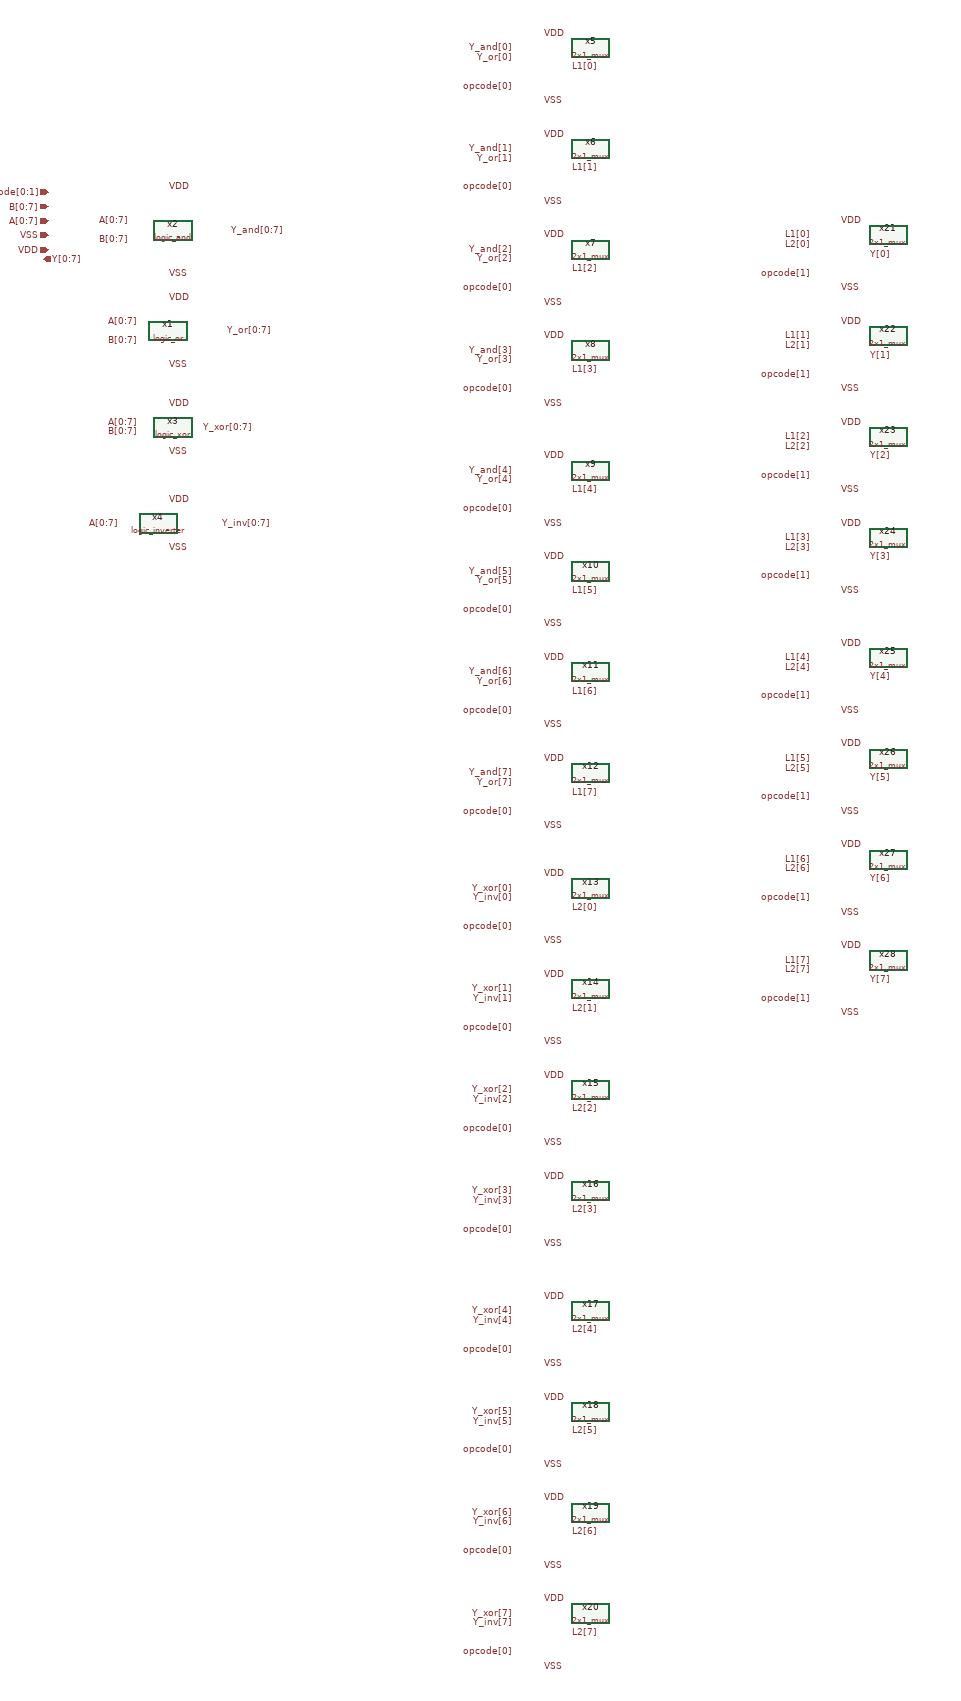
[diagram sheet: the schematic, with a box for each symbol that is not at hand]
v {xschem version=3.1.0 file_version=1.2 }
G {}
K {}
V {}
S {}
E {}
C {logic_or.sym} -820 -830 0 0 {name=x1}
C {logic_and.sym} -810 -1040 0 0 {name=x2}
C {logic_xor.sym} -810 -630 0 0 {name=x3}
C {logic_inverter.sym} -840 -430 0 0 {name=x4}
C {devices/ipin.sym} -1070 -1090 0 0 {name=p4 lab=B[0:7]}
C {devices/opin.sym} -1080 -980 0 0 {name=p9 lab=Y[0:7]}
C {devices/iopin.sym} -1070 -1000 2 0 {name=p2 lab=VDD}
C {devices/iopin.sym} -1070 -1030 2 0 {name=p6 lab=VSS}
C {devices/lab_pin.sym} -900 -1060 0 0 {name=l35 sig_type=std_logic lab=A[0:7]}
C {devices/lab_pin.sym} -900 -1020 0 0 {name=l36 sig_type=std_logic lab=B[0:7]}
C {devices/lab_pin.sym} -880 -850 0 0 {name=l1 sig_type=std_logic lab=A[0:7]}
C {devices/lab_pin.sym} -880 -810 0 0 {name=l2 sig_type=std_logic lab=B[0:7]}
C {devices/lab_pin.sym} -880 -640 0 0 {name=l3 sig_type=std_logic lab=A[0:7]}
C {devices/lab_pin.sym} -880 -620 0 0 {name=l4 sig_type=std_logic lab=B[0:7]}
C {devices/lab_pin.sym} -920 -430 0 0 {name=l5 sig_type=std_logic lab=A[0:7]}
C {devices/lab_pin.sym} -690 -1040 2 0 {name=l37 sig_type=std_logic lab=Y_and[0:7]}
C {devices/lab_pin.sym} -750 -630 2 0 {name=l7 sig_type=std_logic lab=Y_xor[0:7]}
C {devices/lab_pin.sym} -710 -430 2 0 {name=l8 sig_type=std_logic lab=Y_inv[0:7]}
C {devices/lab_pin.sym} -100 -1420 0 0 {name=l9 sig_type=std_logic lab=Y_and[0]}
C {devices/lab_pin.sym} -100 -1210 0 0 {name=l10 sig_type=std_logic lab=Y_and[1]}
C {devices/lab_pin.sym} -100 -1000 0 0 {name=l11 sig_type=std_logic lab=Y_and[2]}
C {devices/lab_pin.sym} -100 -790 0 0 {name=l12 sig_type=std_logic lab=Y_and[3]}
C {devices/lab_pin.sym} -100 -540 0 0 {name=l13 sig_type=std_logic lab=Y_and[4]}
C {devices/lab_pin.sym} -100 -330 0 0 {name=l14 sig_type=std_logic lab=Y_and[5]}
C {devices/lab_pin.sym} -100 -120 0 0 {name=l15 sig_type=std_logic lab=Y_and[6]}
C {devices/lab_pin.sym} -100 90 0 0 {name=l16 sig_type=std_logic lab=Y_and[7]}
C {devices/lab_pin.sym} -100 -1400 0 0 {name=l17 sig_type=std_logic lab=Y_or[0]}
C {devices/lab_pin.sym} -700 -830 2 0 {name=l18 sig_type=std_logic lab=Y_or[0:7]}
C {devices/lab_pin.sym} -100 -1190 0 0 {name=l19 sig_type=std_logic lab=Y_or[1]}
C {devices/lab_pin.sym} -100 -980 0 0 {name=l20 sig_type=std_logic lab=Y_or[2]}
C {devices/lab_pin.sym} -100 -770 0 0 {name=l21 sig_type=std_logic lab=Y_or[3]}
C {devices/lab_pin.sym} -100 -520 0 0 {name=l22 sig_type=std_logic lab=Y_or[4]}
C {devices/lab_pin.sym} -100 -310 0 0 {name=l23 sig_type=std_logic lab=Y_or[5]}
C {devices/lab_pin.sym} -100 -100 0 0 {name=l24 sig_type=std_logic lab=Y_or[6]}
C {devices/lab_pin.sym} -100 110 0 0 {name=l25 sig_type=std_logic lab=Y_or[7]}
C {devices/ipin.sym} -1070 -1120 0 0 {name=p5 lab=opcode[0:1]}
C {devices/lab_pin.sym} -100 -1340 0 0 {name=l26 sig_type=std_logic lab=opcode[0]}
C {devices/lab_pin.sym} -100 -1130 0 0 {name=l27 sig_type=std_logic lab=opcode[0]}
C {devices/lab_pin.sym} -100 -920 0 0 {name=l28 sig_type=std_logic lab=opcode[0]}
C {devices/lab_pin.sym} -100 -710 0 0 {name=l29 sig_type=std_logic lab=opcode[0]}
C {devices/lab_pin.sym} -100 -460 0 0 {name=l30 sig_type=std_logic lab=opcode[0]}
C {devices/lab_pin.sym} -100 -250 0 0 {name=l31 sig_type=std_logic lab=opcode[0]}
C {devices/lab_pin.sym} -100 -40 0 0 {name=l32 sig_type=std_logic lab=opcode[0]}
C {devices/lab_pin.sym} -100 170 0 0 {name=l33 sig_type=std_logic lab=opcode[0]}
C {devices/lab_pin.sym} -100 410 0 0 {name=l34 sig_type=std_logic lab=opcode[0]}
C {devices/lab_pin.sym} -100 620 0 0 {name=l38 sig_type=std_logic lab=opcode[0]}
C {devices/lab_pin.sym} -100 830 0 0 {name=l39 sig_type=std_logic lab=opcode[0]}
C {devices/lab_pin.sym} -100 1040 0 0 {name=l40 sig_type=std_logic lab=opcode[0]}
C {devices/lab_pin.sym} -100 1290 0 0 {name=l41 sig_type=std_logic lab=opcode[0]}
C {devices/lab_pin.sym} -100 1500 0 0 {name=l42 sig_type=std_logic lab=opcode[0]}
C {devices/lab_pin.sym} -100 1710 0 0 {name=l43 sig_type=std_logic lab=opcode[0]}
C {devices/lab_pin.sym} -100 1920 0 0 {name=l44 sig_type=std_logic lab=opcode[0]}
C {devices/lab_pin.sym} -100 330 0 0 {name=l45 sig_type=std_logic lab=Y_xor[0]}
C {devices/lab_pin.sym} -100 540 0 0 {name=l46 sig_type=std_logic lab=Y_xor[1]}
C {devices/lab_pin.sym} -100 750 0 0 {name=l47 sig_type=std_logic lab=Y_xor[2]}
C {devices/lab_pin.sym} -100 960 0 0 {name=l48 sig_type=std_logic lab=Y_xor[3]}
C {devices/lab_pin.sym} -100 1210 0 0 {name=l49 sig_type=std_logic lab=Y_xor[4]}
C {devices/lab_pin.sym} -100 1420 0 0 {name=l50 sig_type=std_logic lab=Y_xor[5]}
C {devices/lab_pin.sym} -100 1630 0 0 {name=l51 sig_type=std_logic lab=Y_xor[6]}
C {devices/lab_pin.sym} -100 1840 0 0 {name=l52 sig_type=std_logic lab=Y_xor[7]}
C {devices/lab_pin.sym} -100 350 0 0 {name=l53 sig_type=std_logic lab=Y_inv[0]}
C {devices/lab_pin.sym} -100 560 0 0 {name=l54 sig_type=std_logic lab=Y_inv[1]}
C {devices/lab_pin.sym} -100 770 0 0 {name=l55 sig_type=std_logic lab=Y_inv[2]}
C {devices/lab_pin.sym} -100 980 0 0 {name=l56 sig_type=std_logic lab=Y_inv[3]}
C {devices/lab_pin.sym} -100 1230 0 0 {name=l57 sig_type=std_logic lab=Y_inv[4]}
C {devices/lab_pin.sym} -100 1440 0 0 {name=l58 sig_type=std_logic lab=Y_inv[5]}
C {devices/lab_pin.sym} -100 1650 0 0 {name=l59 sig_type=std_logic lab=Y_inv[6]}
C {devices/lab_pin.sym} -100 1860 0 0 {name=l60 sig_type=std_logic lab=Y_inv[7]}
C {devices/lab_pin.sym} 520 -950 0 0 {name=l61 sig_type=std_logic lab=opcode[1]}
C {devices/lab_pin.sym} 520 -740 0 0 {name=l62 sig_type=std_logic lab=opcode[1]}
C {devices/lab_pin.sym} 520 -530 0 0 {name=l63 sig_type=std_logic lab=opcode[1]}
C {devices/lab_pin.sym} 520 -320 0 0 {name=l64 sig_type=std_logic lab=opcode[1]}
C {devices/lab_pin.sym} 520 -70 0 0 {name=l65 sig_type=std_logic lab=opcode[1]}
C {devices/lab_pin.sym} 520 140 0 0 {name=l66 sig_type=std_logic lab=opcode[1]}
C {devices/lab_pin.sym} 520 350 0 0 {name=l67 sig_type=std_logic lab=opcode[1]}
C {devices/lab_pin.sym} 520 560 0 0 {name=l68 sig_type=std_logic lab=opcode[1]}
C {devices/lab_pin.sym} 20 580 2 0 {name=l70 sig_type=std_logic lab=L2[1]}
C {devices/lab_pin.sym} 20 790 2 0 {name=l71 sig_type=std_logic lab=L2[2]}
C {devices/lab_pin.sym} 20 1000 2 0 {name=l72 sig_type=std_logic lab=L2[3]}
C {devices/lab_pin.sym} 20 1250 2 0 {name=l73 sig_type=std_logic lab=L2[4]}
C {devices/lab_pin.sym} 20 1460 2 0 {name=l74 sig_type=std_logic lab=L2[5]}
C {devices/lab_pin.sym} 20 1670 2 0 {name=l75 sig_type=std_logic lab=L2[6]}
C {devices/lab_pin.sym} 20 1880 2 0 {name=l76 sig_type=std_logic lab=L2[7]}
C {devices/lab_pin.sym} 520 500 0 0 {name=l77 sig_type=std_logic lab=L2[7]}
C {devices/lab_pin.sym} 520 290 0 0 {name=l78 sig_type=std_logic lab=L2[6]}
C {devices/lab_pin.sym} 520 80 0 0 {name=l79 sig_type=std_logic lab=L2[5]}
C {devices/lab_pin.sym} 520 -130 0 0 {name=l80 sig_type=std_logic lab=L2[4]}
C {devices/lab_pin.sym} 520 -380 0 0 {name=l81 sig_type=std_logic lab=L2[3]}
C {devices/lab_pin.sym} 520 -590 0 0 {name=l82 sig_type=std_logic lab=L2[2]}
C {devices/lab_pin.sym} 520 -800 0 0 {name=l83 sig_type=std_logic lab=L2[1]}
C {devices/lab_pin.sym} 520 -1010 0 0 {name=l84 sig_type=std_logic lab=L2[0]}
C {devices/lab_pin.sym} 20 370 2 0 {name=l85 sig_type=std_logic lab=L2[0]}
C {devices/lab_pin.sym} 20 -1170 2 0 {name=l87 sig_type=std_logic lab=L1[1]}
C {devices/lab_pin.sym} 20 -960 2 0 {name=l88 sig_type=std_logic lab=L1[2]}
C {devices/lab_pin.sym} 20 -750 2 0 {name=l89 sig_type=std_logic lab=L1[3]}
C {devices/lab_pin.sym} 20 -500 2 0 {name=l90 sig_type=std_logic lab=L1[4]}
C {devices/lab_pin.sym} 20 -290 2 0 {name=l91 sig_type=std_logic lab=L1[5]}
C {devices/lab_pin.sym} 20 -80 2 0 {name=l92 sig_type=std_logic lab=L1[6]}
C {devices/lab_pin.sym} 20 130 2 0 {name=l93 sig_type=std_logic lab=L1[7]}
C {devices/lab_pin.sym} 520 -820 0 0 {name=l69 sig_type=std_logic lab=L1[1]}
C {devices/lab_pin.sym} 520 -610 0 0 {name=l94 sig_type=std_logic lab=L1[2]}
C {devices/lab_pin.sym} 520 -400 0 0 {name=l95 sig_type=std_logic lab=L1[3]}
C {devices/lab_pin.sym} 520 -150 0 0 {name=l96 sig_type=std_logic lab=L1[4]}
C {devices/lab_pin.sym} 520 60 0 0 {name=l97 sig_type=std_logic lab=L1[5]}
C {devices/lab_pin.sym} 520 270 0 0 {name=l98 sig_type=std_logic lab=L1[6]}
C {devices/lab_pin.sym} 520 480 0 0 {name=l99 sig_type=std_logic lab=L1[7]}
C {devices/lab_pin.sym} 20 -1380 2 0 {name=l6 sig_type=std_logic lab=L1[0]}
C {devices/lab_pin.sym} 520 -1030 0 0 {name=l86 sig_type=std_logic lab=L1[0]}
C {devices/lab_pin.sym} 640 -990 2 0 {name=l100 sig_type=std_logic lab=Y[0]}
C {devices/lab_pin.sym} 640 -780 2 0 {name=l101 sig_type=std_logic lab=Y[1]}
C {devices/lab_pin.sym} 640 -570 2 0 {name=l102 sig_type=std_logic lab=Y[2]}
C {devices/lab_pin.sym} 640 -360 2 0 {name=l103 sig_type=std_logic lab=Y[3]}
C {devices/lab_pin.sym} 640 -110 2 0 {name=l104 sig_type=std_logic lab=Y[4]}
C {devices/lab_pin.sym} 640 100 2 0 {name=l105 sig_type=std_logic lab=Y[5]}
C {devices/lab_pin.sym} 640 310 2 0 {name=l106 sig_type=std_logic lab=Y[6]}
C {devices/lab_pin.sym} 640 520 2 0 {name=l107 sig_type=std_logic lab=Y[7]}
C {devices/lab_pin.sym} -820 -1130 2 0 {name=l108 sig_type=std_logic lab=VDD}
C {devices/lab_pin.sym} -820 -680 2 0 {name=l110 sig_type=std_logic lab=VDD}
C {devices/lab_pin.sym} -820 -900 2 0 {name=l109 sig_type=std_logic lab=VDD}
C {devices/lab_pin.sym} -820 -480 2 0 {name=l111 sig_type=std_logic lab=VDD}
C {devices/lab_pin.sym} -40 -1450 2 0 {name=l112 sig_type=std_logic lab=VDD}
C {devices/lab_pin.sym} -40 -1240 2 0 {name=l113 sig_type=std_logic lab=VDD}
C {devices/lab_pin.sym} -40 -1030 2 0 {name=l114 sig_type=std_logic lab=VDD}
C {devices/lab_pin.sym} -40 -820 2 0 {name=l115 sig_type=std_logic lab=VDD}
C {devices/lab_pin.sym} -40 -570 2 0 {name=l116 sig_type=std_logic lab=VDD}
C {devices/lab_pin.sym} -40 -360 2 0 {name=l117 sig_type=std_logic lab=VDD}
C {devices/lab_pin.sym} -40 -150 2 0 {name=l118 sig_type=std_logic lab=VDD}
C {devices/lab_pin.sym} -40 60 2 0 {name=l119 sig_type=std_logic lab=VDD}
C {devices/lab_pin.sym} -40 300 2 0 {name=l120 sig_type=std_logic lab=VDD}
C {devices/lab_pin.sym} -40 510 2 0 {name=l121 sig_type=std_logic lab=VDD}
C {devices/lab_pin.sym} -40 720 2 0 {name=l122 sig_type=std_logic lab=VDD}
C {devices/lab_pin.sym} -40 930 2 0 {name=l123 sig_type=std_logic lab=VDD}
C {devices/lab_pin.sym} -40 1180 2 0 {name=l124 sig_type=std_logic lab=VDD}
C {devices/lab_pin.sym} -40 1390 2 0 {name=l125 sig_type=std_logic lab=VDD}
C {devices/lab_pin.sym} -40 1600 2 0 {name=l126 sig_type=std_logic lab=VDD}
C {devices/lab_pin.sym} -40 1810 2 0 {name=l127 sig_type=std_logic lab=VDD}
C {devices/lab_pin.sym} 580 -1060 2 0 {name=l128 sig_type=std_logic lab=VDD}
C {devices/lab_pin.sym} 580 -850 2 0 {name=l129 sig_type=std_logic lab=VDD}
C {devices/lab_pin.sym} 580 -640 2 0 {name=l130 sig_type=std_logic lab=VDD}
C {devices/lab_pin.sym} 580 -430 2 0 {name=l131 sig_type=std_logic lab=VDD}
C {devices/lab_pin.sym} 580 -180 2 0 {name=l132 sig_type=std_logic lab=VDD}
C {devices/lab_pin.sym} 580 30 2 0 {name=l133 sig_type=std_logic lab=VDD}
C {devices/lab_pin.sym} 580 240 2 0 {name=l134 sig_type=std_logic lab=VDD}
C {devices/lab_pin.sym} 580 450 2 0 {name=l135 sig_type=std_logic lab=VDD}
C {devices/lab_pin.sym} -820 -950 2 0 {name=l136 sig_type=std_logic lab=VSS}
C {devices/lab_pin.sym} -820 -760 2 0 {name=l137 sig_type=std_logic lab=VSS}
C {devices/lab_pin.sym} -820 -580 2 0 {name=l138 sig_type=std_logic lab=VSS}
C {devices/lab_pin.sym} -820 -380 2 0 {name=l139 sig_type=std_logic lab=VSS}
C {devices/lab_pin.sym} -40 -1310 2 0 {name=l140 sig_type=std_logic lab=VSS}
C {devices/lab_pin.sym} -40 -1100 2 0 {name=l141 sig_type=std_logic lab=VSS}
C {devices/lab_pin.sym} -40 -890 2 0 {name=l142 sig_type=std_logic lab=VSS}
C {devices/lab_pin.sym} -40 -680 2 0 {name=l143 sig_type=std_logic lab=VSS}
C {devices/lab_pin.sym} -40 -430 2 0 {name=l144 sig_type=std_logic lab=VSS}
C {devices/lab_pin.sym} -40 -220 2 0 {name=l145 sig_type=std_logic lab=VSS}
C {devices/lab_pin.sym} -40 -10 2 0 {name=l146 sig_type=std_logic lab=VSS}
C {devices/lab_pin.sym} -40 200 2 0 {name=l147 sig_type=std_logic lab=VSS}
C {devices/lab_pin.sym} -40 440 2 0 {name=l148 sig_type=std_logic lab=VSS}
C {devices/lab_pin.sym} -40 650 2 0 {name=l149 sig_type=std_logic lab=VSS}
C {devices/lab_pin.sym} -40 860 2 0 {name=l150 sig_type=std_logic lab=VSS}
C {devices/lab_pin.sym} -40 1070 2 0 {name=l151 sig_type=std_logic lab=VSS}
C {devices/lab_pin.sym} -40 1320 2 0 {name=l152 sig_type=std_logic lab=VSS}
C {devices/lab_pin.sym} -40 1530 2 0 {name=l153 sig_type=std_logic lab=VSS}
C {devices/lab_pin.sym} -40 1740 2 0 {name=l154 sig_type=std_logic lab=VSS}
C {devices/lab_pin.sym} -40 1950 2 0 {name=l155 sig_type=std_logic lab=VSS}
C {devices/lab_pin.sym} 580 590 2 0 {name=l156 sig_type=std_logic lab=VSS}
C {devices/lab_pin.sym} 580 380 2 0 {name=l157 sig_type=std_logic lab=VSS}
C {devices/lab_pin.sym} 580 170 2 0 {name=l158 sig_type=std_logic lab=VSS}
C {devices/lab_pin.sym} 580 -40 2 0 {name=l159 sig_type=std_logic lab=VSS}
C {devices/lab_pin.sym} 580 -290 2 0 {name=l160 sig_type=std_logic lab=VSS}
C {devices/lab_pin.sym} 580 -500 2 0 {name=l161 sig_type=std_logic lab=VSS}
C {devices/lab_pin.sym} 580 -710 2 0 {name=l162 sig_type=std_logic lab=VSS}
C {devices/lab_pin.sym} 580 -920 2 0 {name=l163 sig_type=std_logic lab=VSS}
C {devices/ipin.sym} -1070 -1060 0 0 {name=p1 lab=A[0:7]}
C {2x1_mux.sym} 60 -1420 0 0 {name=x5}
C {2x1_mux.sym} 60 -1210 0 0 {name=x6}
C {2x1_mux.sym} 60 -1000 0 0 {name=x7}
C {2x1_mux.sym} 60 -790 0 0 {name=x8}
C {2x1_mux.sym} 60 -540 0 0 {name=x9}
C {2x1_mux.sym} 60 -330 0 0 {name=x10}
C {2x1_mux.sym} 60 -120 0 0 {name=x11}
C {2x1_mux.sym} 60 90 0 0 {name=x12}
C {2x1_mux.sym} 60 330 0 0 {name=x13}
C {2x1_mux.sym} 60 540 0 0 {name=x14}
C {2x1_mux.sym} 60 750 0 0 {name=x15}
C {2x1_mux.sym} 60 960 0 0 {name=x16}
C {2x1_mux.sym} 60 1210 0 0 {name=x17}
C {2x1_mux.sym} 60 1420 0 0 {name=x18}
C {2x1_mux.sym} 60 1630 0 0 {name=x19}
C {2x1_mux.sym} 60 1840 0 0 {name=x20}
C {2x1_mux.sym} 680 -1030 0 0 {name=x21}
C {2x1_mux.sym} 680 -820 0 0 {name=x22}
C {2x1_mux.sym} 680 -610 0 0 {name=x23}
C {2x1_mux.sym} 680 -400 0 0 {name=x24}
C {2x1_mux.sym} 680 -150 0 0 {name=x25}
C {2x1_mux.sym} 680 60 0 0 {name=x26}
C {2x1_mux.sym} 680 270 0 0 {name=x27}
C {2x1_mux.sym} 680 480 0 0 {name=x28}
